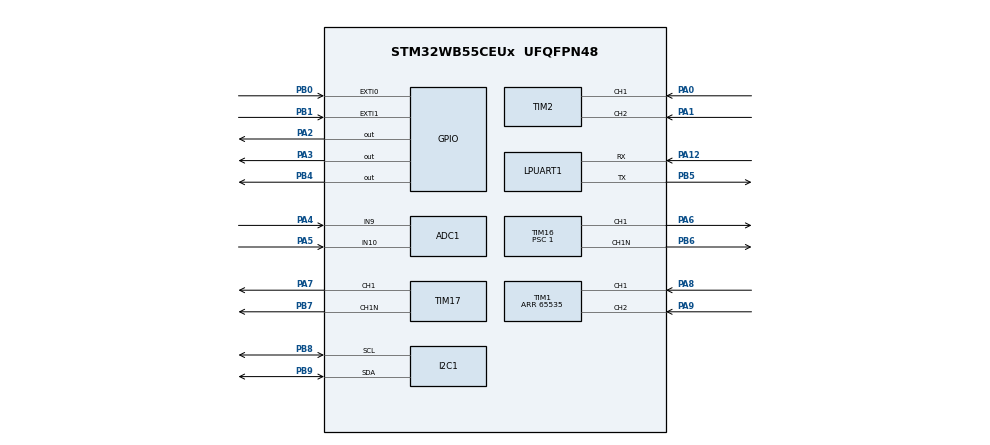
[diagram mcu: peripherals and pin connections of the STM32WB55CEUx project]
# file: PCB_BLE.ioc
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ADC1.Channel-0\#ChannelRegularConversion=ADC_CHANNEL_9
ADC1.Channel-1\#ChannelRegularConversion=ADC_CHANNEL_10
ADC1.ContinuousConvMode=ENABLE
ADC1.DMAContinuousRequests=ENABLE
ADC1.NbrOfConversion=2
ADC1.NbrOfConversionFlag=1
ADC1.OffsetNumber-0\#ChannelRegularConversion=ADC_OFFSET_NONE
ADC1.OffsetNumber-1\#ChannelRegularConversion=ADC_OFFSET_NONE
ADC1.Rank-0\#ChannelRegularConversion=1
ADC1.Rank-1\#ChannelRegularConversion=2
ADC1.SamplingTime-0\#ChannelRegularConversion=ADC_SAMPLETIME_640CYCLES_5
ADC1.SamplingTime-1\#ChannelRegularConversion=ADC_SAMPLETIME_640CYCLES_5
ADC1.master=1
Dma.ADC1.0.Direction=DMA_PERIPH_TO_MEMORY
Dma.ADC1.0.EventEnable=DISABLE
Dma.ADC1.0.Instance=DMA1_Channel1
Dma.ADC1.0.MemDataAlignment=DMA_MDATAALIGN_HALFWORD
Dma.ADC1.0.MemInc=DMA_MINC_ENABLE
Dma.ADC1.0.Mode=DMA_CIRCULAR
Dma.ADC1.0.PeriphDataAlignment=DMA_PDATAALIGN_HALFWORD
Dma.ADC1.0.PeriphInc=DMA_PINC_DISABLE
Dma.ADC1.0.Polarity=HAL_DMAMUX_REQ_GEN_RISING
Dma.ADC1.0.Priority=DMA_PRIORITY_LOW
Dma.ADC1.0.RequestNumber=1
Dma.ADC1.0.SignalID=NONE
Dma.ADC1.0.SyncEnable=DISABLE
Dma.ADC1.0.SyncPolarity=HAL_DMAMUX_SYNC_NO_EVENT
Dma.ADC1.0.SyncRequestNumber=1
Dma.ADC1.0.SyncSignalID=NONE
Dma.Request0=ADC1
FREERTOS.Tasks01=defaultTask,24,128,StartDefaultTask,Default,NULL,Dynamic,NULL,NULL
FREERTOS.configTOTAL_HEAP_SIZE=5000
I2C1.Timing=0x00B07CB4
LPTIM1.ClockPrescaler=LPTIM_PRESCALER_DIV128
Mcu.Family=STM32WB
Mcu.Name=STM32WB55CEUx
Mcu.Package=UFQFPN48
NVIC.ADC1_IRQn=true\:5\:0\:false\:false\:true\:true\:true\:true\:true
NVIC.DMA1_Channel1_IRQn=true\:5\:0\:false\:false\:true\:true\:false\:true\:true
NVIC.EXTI0_IRQn=true\:5\:0\:false\:false\:true\:true\:true\:true\:true
NVIC.HSEM_IRQn=true\:5\:0\:false\:false\:true\:true\:false\:true\:true
NVIC.IPCC_C1_RX_IRQn=true\:5\:0\:false\:false\:true\:true\:true\:true\:true
NVIC.IPCC_C1_TX_IRQn=true\:5\:0\:false\:false\:true\:true\:true\:true\:true
NVIC.LPTIM1_IRQn=true\:5\:0\:false\:false\:true\:true\:true\:true\:true
NVIC.PriorityGroup=NVIC_PRIORITYGROUP_4
NVIC.RTC_WKUP_IRQn=true\:5\:0\:false\:false\:true\:true\:true\:true\:true
OSC_IN.Mode=HSE-External-Oscillator
OSC_IN.Signal=RCC_OSC_IN
OSC_OUT.Mode=HSE-External-Oscillator
OSC_OUT.Signal=RCC_OSC_OUT
PA0.Signal=S_TIM2_CH1
PA1.Signal=S_TIM2_CH2
PA12.Mode=Asynchronous
PA12.Signal=LPUART1_RX
PA13.Mode=Serial_Wire
PA13.Signal=SYS_JTMS-SWDIO
PA14.Mode=Serial_Wire
PA14.Signal=SYS_JTCK-SWCLK
PA2.Signal=GPIO_Output
PA3.Signal=GPIO_Output
PA4.Signal=ADCx_IN9
PA5.Signal=ADCx_IN10
PA6.Signal=S_TIM16_CH1
PA7.Signal=S_TIM17_CH1
PA8.Signal=S_TIM1_CH1
PA9.Signal=S_TIM1_CH2
PB0.Signal=GPXTI0
PB1.Signal=GPXTI1
PB3.Signal=SYS_JTDO-SWO
PB4.Signal=GPIO_Output
PB5.Mode=Asynchronous
PB5.Signal=LPUART1_TX
PB6.Mode=PWM Generation1 CH1 CH1N
PB6.Signal=TIM16_CH1N
PB7.Mode=PWM Generation1 CH1 CH1N
PB7.Signal=TIM17_CH1N
PB8.Mode=I2C
PB8.Signal=I2C1_SCL
PB9.Mode=I2C
PB9.Signal=I2C1_SDA
PC14-OSC32_IN.Mode=LSE-External-Oscillator
PC14-OSC32_IN.Signal=RCC_OSC32_IN
PC15-OSC32_OUT.Mode=LSE-External-Oscillator
PC15-OSC32_OUT.Signal=RCC_OSC32_OUT
ProjectManager.HeapSize=0x200
ProjectManager.StackSize=0x400
ProjectManager.TargetToolchain=STM32CubeIDE
RCC.ADCFreq_Value=48000000
RCC.AHBFreq_Value=32000000
RCC.APB1Freq_Value=32000000
RCC.APB1TimFreq_Value=32000000
RCC.APB2Freq_Value=32000000
RCC.APB2TimFreq_Value=32000000
RCC.APB3Freq_Value=16000000
RCC.CortexFreq_Value=32000000
RCC.HCLKFreq_Value=32000000
RCC.HSE_VALUE=32000000
RCC.HSI48_VALUE=48000000
RCC.HSI_VALUE=16000000
RCC.PLLN=24
RCC.PLLR=RCC_PLLR_DIV3
RCC.PLLSAI1N=24
RCC.SYSCLKFreq_VALUE=32000000
RCC.SYSCLKSource=RCC_SYSCLKSOURCE_PLLCLK
RCC.USBFreq_Value=48000000
RCC.VCOOutputFreq_Value=96000000
RF1.Mode=RF1_Activate
RF1.Signal=RF_RF1
SH.ADCx_IN10.0=ADC1_IN10,IN10-Single-Ended
SH.ADCx_IN9.0=ADC1_IN9,IN9-Single-Ended
SH.S_TIM16_CH1.0=TIM16_CH1,PWM Generation1 CH1 CH1N
SH.S_TIM17_CH1.0=TIM17_CH1,PWM Generation1 CH1 CH1N
SH.S_TIM1_CH1.0=TIM1_CH1,Encoder_Interface
SH.S_TIM1_CH2.0=TIM1_CH2,Encoder_Interface
SH.S_TIM2_CH1.0=TIM2_CH1,Encoder_Interface
SH.S_TIM2_CH2.0=TIM2_CH2,Encoder_Interface
STM32_WPAN.BLE_DBG_APP_EN=1
STM32_WPAN.BLE_DBG_DIS_EN=1
STM32_WPAN.BLE_DBG_HRS_EN=1
STM32_WPAN.BLE_DBG_SVCCTL_EN=1
TIM1.AutoReloadPreload=TIM_AUTORELOAD_PRELOAD_ENABLE
TIM1.EncoderMode=TIM_ENCODERMODE_TI12
TIM1.IC1Filter=10
TIM1.Period=65535
TIM16.Channel=TIM_CHANNEL_1
TIM16.Period=1000-1
TIM16.Prescaler=1
TIM16.Pulse=0
TIM17.Channel=TIM_CHANNEL_1
VP_FREERTOS_VS_CMSIS_V2.Mode=CMSIS_V2
VP_HSEM_VS_HSEM.Mode=HSEM_Activate
VP_IPCC_VS_IPCC.Mode=IPCC_Activate
VP_LPTIM1_VS_LPTIM_counterModeInternalClock.Mode=Counts__internal_clock_event_00
VP_MEMORYMAP_VS_MEMORYMAP.Mode=CurAppReg
VP_RTC_VS_RTC_Activate.Mode=RTC_Enabled
VP_RTC_VS_RTC_WakeUp_intern.Mode=WakeUp
VP_STM32_WPAN_VS_BLE_HOST.Mode=STM32_WPAN_Enabled
VP_TIM16_VS_ClockSourceINT.Mode=Enable_Timer
VP_TIM17_VS_ClockSourceINT.Mode=Enable_Timer
VP_TINY_LPM_VS_TINY_LPM.Mode=TINY_LPM_Enabled
board=custom

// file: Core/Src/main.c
/* USER CODE BEGIN Header */
/**
  ******************************************************************************
  * @file           : main.c
  * @brief          : Main program body
  ******************************************************************************
  * @attention
  *
  * Copyright (c) 2025 STMicroelectronics.
  * All rights reserved.
  *
  * This software is licensed under terms that can be found in the LICENSE file
  * in the root directory of this software component.
  * If no LICENSE file comes with this software, it is provided AS-IS.
  *
  ******************************************************************************
  */
/* USER CODE END Header */
#include "main.h"
#include "cmsis_os.h"
#include "adc.h"
#include "dma.h"
#include "i2c.h"
#include "ipcc.h"
#include "lptim.h"
#include "usart.h"
#include "rf.h"
#include "rtc.h"
#include "tim.h"
#include "gpio.h"

/* USER CODE BEGIN Includes */
#include "timers.h"
#include "cmsis_os2.h"
#include "app_common.h"
#include <string.h>
#include "app_common.h"
#include "ble.h"
#include "ble_types.h"
#include "ble_const.h"
#include "ble_gap_aci.h"
#include "ble_gatt_aci.h"
#include "hci_tl.h"
#include "hrs_app.h"
#include "VL53L0X.h"
#include "stdio.h"
#include "sensor.h"
#include "moteur.h"
#include "LIDAR.h"
// ---------- Prototypes ----------
void SensorTask(void *argument);
void BleTask(void *argument);
/* USER CODE END Includes */

/* USER CODE BEGIN PTD */

extern osThreadId_t sensorTaskHandle;
extern osThreadId_t odomTaskHandle;
extern osThreadId_t lidarTaskHandle;
extern osThreadId_t defaultTaskHandle;
extern osThreadId_t TOFTaskHandle;
extern osThreadId_t comTaskHandle;

HAL_StatusTypeDef ID_SENSOR;
uint16_t position ;

extern Position pos ;

extern uint16_t distance;
extern statInfo_t_VL53L0X distanceStr;
System_state state = {0};
TOF capteur_tof ;
#define LPTIM_PERIOD_10MS 2500

volatile uint8_t dma_byte_buf[DMA_BYTE_BUF_SIZE];
Pos vue[N_ANGLES];  // tableau final des distances en mm
Cluster clusters[MAX_CLUSTERS];

int* last_count_g = 0;
int* last_count_d = 0;

/* USER CODE END PTD */

void SystemClock_Config(void);
void PeriphCommonClock_Config(void);
void MX_FREERTOS_Init(void);

int main(void)
{

  /* USER CODE BEGIN 1 */
	char msgBuffer[52];
	for (int i = 0; i < 52; i++) {
		msgBuffer[i] = ' ';
	}
  /* USER CODE END 1 */

  /* MCU Configuration--------------------------------------------------------*/

  /* Reset of all peripherals, Initializes the Flash interface and the Systick. */
  HAL_Init();
  /* Config code for STM32_WPAN (HSE Tuning must be done before system clock configuration) */
  MX_APPE_Config();

  /* Configure the system clock */
  SystemClock_Config();

  /* Configure the peripherals common clocks */
  PeriphCommonClock_Config();

  /* IPCC initialisation */
  MX_IPCC_Init();

  /* Initialize all configured peripherals */
  MX_GPIO_Init();
  MX_DMA_Init();
  MX_ADC1_Init();
  MX_LPTIM1_Init();
  MX_RTC_Init();
  MX_TIM1_Init();
  MX_TIM2_Init();
  MX_TIM16_Init();
  MX_TIM17_Init();
  MX_I2C1_Init();
  MX_LPUART1_UART_Init();
  MX_RF_Init();
  /* USER CODE BEGIN 2 */
  ID_SENSOR = ADXL343_Init();
  if (ID_SENSOR == HAL_OK)
  {
	  for (int i = 0;i<10;i++)
	  {
		   HAL_GPIO_TogglePin(GPIOA, GPIO_PIN_2);
		   //HAL_Delay(300);
	  }
  }

  ID_SENSOR = TCA9548A_Init();
    if (ID_SENSOR != HAL_OK)
    {
  	  for (int i = 0;i<20;i++)
  	  {
  		   HAL_GPIO_TogglePin(GPIOA, GPIO_PIN_2);
  		   //HAL_Delay(150);
  	  }
    }

  //Initialise the 4th TOF
  INIT_TOFS(&hi2c1);
  ///////
  CoreDebug->DEMCR |= CoreDebug_DEMCR_TRCENA_Msk;  // Active TRC
  DWT->CYCCNT = 0;                                  // Reset counter
  DWT->CTRL |= DWT_CTRL_CYCCNTENA_Msk;              // Active CYCCNT
  //Motor_Init();
  //Motor_Forward(500);
 // Motor_Ramp_L(&state, 600, 4);

  if (HAL_LPTIM_Counter_Start_IT(&hlptim1,LPTIM_PERIOD_10MS) != HAL_OK)
  {
      Error_Handler();
  }
  Encoder_Init();
  HAL_UART_Receive_DMA(&hlpuart1, (uint8_t *)dma_byte_buf, DMA_BYTE_BUF_SIZE);

  /* USER CODE END 2 */

  /* Init scheduler */
  osKernelInitialize();
  /* Init code for STM32_WPAN */
  MX_APPE_Init();
  /* Call init function for freertos objects (in cmsis_os2.c) */
  MX_FREERTOS_Init();

  /* Start scheduler */
  osKernelStart();

  /* We should never get here as control is now taken by the scheduler */

  /* Infinite loop */
  while (1)
  {

	}
}

void SystemClock_Config(void)
{
  RCC_OscInitTypeDef RCC_OscInitStruct = {0};
  RCC_ClkInitTypeDef RCC_ClkInitStruct = {0};

  /** Configure the main internal regulator output voltage
  */
  __HAL_PWR_VOLTAGESCALING_CONFIG(PWR_REGULATOR_VOLTAGE_SCALE1);

  /** Initializes the RCC Oscillators according to the specified parameters
  * in the RCC_OscInitTypeDef structure.
  */
  RCC_OscInitStruct.OscillatorType = RCC_OSCILLATORTYPE_HSI|RCC_OSCILLATORTYPE_LSI1
                              |RCC_OSCILLATORTYPE_HSE;
  RCC_OscInitStruct.HSEState = RCC_HSE_ON;
  RCC_OscInitStruct.HSIState = RCC_HSI_ON;
  RCC_OscInitStruct.HSICalibrationValue = RCC_HSICALIBRATION_DEFAULT;
  RCC_OscInitStruct.LSIState = RCC_LSI_ON;
  RCC_OscInitStruct.PLL.PLLState = RCC_PLL_ON;
  RCC_OscInitStruct.PLL.PLLSource = RCC_PLLSOURCE_HSE;
  RCC_OscInitStruct.PLL.PLLM = RCC_PLLM_DIV4;
  RCC_OscInitStruct.PLL.PLLN = 24;
  RCC_OscInitStruct.PLL.PLLP = RCC_PLLP_DIV2;
  RCC_OscInitStruct.PLL.PLLR = RCC_PLLR_DIV3;
  RCC_OscInitStruct.PLL.PLLQ = RCC_PLLQ_DIV2;
  if (HAL_RCC_OscConfig(&RCC_OscInitStruct) != HAL_OK)
  {
    Error_Handler();
  }

  /** Configure the SYSCLKSource, HCLK, PCLK1 and PCLK2 clocks dividers
  */
  RCC_ClkInitStruct.ClockType = RCC_CLOCKTYPE_HCLK4|RCC_CLOCKTYPE_HCLK2
                              |RCC_CLOCKTYPE_HCLK|RCC_CLOCKTYPE_SYSCLK
                              |RCC_CLOCKTYPE_PCLK1|RCC_CLOCKTYPE_PCLK2;
  RCC_ClkInitStruct.SYSCLKSource = RCC_SYSCLKSOURCE_PLLCLK;
  RCC_ClkInitStruct.AHBCLKDivider = RCC_SYSCLK_DIV1;
  RCC_ClkInitStruct.APB1CLKDivider = RCC_HCLK_DIV1;
  RCC_ClkInitStruct.APB2CLKDivider = RCC_HCLK_DIV1;
  RCC_ClkInitStruct.AHBCLK2Divider = RCC_SYSCLK_DIV2;
  RCC_ClkInitStruct.AHBCLK4Divider = RCC_SYSCLK_DIV1;

  if (HAL_RCC_ClockConfig(&RCC_ClkInitStruct, FLASH_LATENCY_3) != HAL_OK)
  {
    Error_Handler();
  }
}

void PeriphCommonClock_Config(void)
{
  RCC_PeriphCLKInitTypeDef PeriphClkInitStruct = {0};

  /** Initializes the peripherals clock
  */
  PeriphClkInitStruct.PeriphClockSelection = RCC_PERIPHCLK_SMPS|RCC_PERIPHCLK_RFWAKEUP;
  PeriphClkInitStruct.RFWakeUpClockSelection = RCC_RFWKPCLKSOURCE_HSE_DIV1024;
  PeriphClkInitStruct.SmpsClockSelection = RCC_SMPSCLKSOURCE_HSI;
  PeriphClkInitStruct.SmpsDivSelection = RCC_SMPSCLKDIV_RANGE1;

  if (HAL_RCCEx_PeriphCLKConfig(&PeriphClkInitStruct) != HAL_OK)
  {
    Error_Handler();
  }
}

/* USER CODE BEGIN 4 */
void HAL_ADC_ConvCpltCallback(ADC_HandleTypeDef* hadc)
{
    if (hadc->Instance == ADC1)
    {
    }
}
extern osSemaphoreId_t i2cSem;
extern osSemaphoreId_t chockSem;
extern osSemaphoreId_t UARTSem;

void HAL_UART_RxCpltCallback(UART_HandleTypeDef *huart)
{
    if(huart->Instance == LPUART1)
    {
  	  osSemaphoreRelease(UARTSem);
    }
}

void HAL_LPTIM_AutoReloadMatchCallback(LPTIM_HandleTypeDef *hlptim)
{
    if (hlptim->Instance == LPTIM1)
    {
    	  //Control_Speed(10.0f,0.01);

    	//Update_Encoder_Vitesse(pos,&last_count_d,&last_count_g);

    	/*
    	// PID gauche
		float u_g = PID_Update(&pid_vitesse_G, pid_vitesse_G, pos.Vitesse_G, 0.001f);
		int pwm_g = (int)(500 + u_g * 500);
		__HAL_TIM_SET_COMPARE(&htim1, TIM_CHANNEL_1, pwm_g);

		// PID droit
		float u_d = PID_Update(&pid_vitesse_D, pid_vitesse_D, pos.Vitesse_D, 0.001f);
		int pwm_d = (int)(500 + u_d * 500);
		__HAL_TIM_SET_COMPARE(&htim2, TIM_CHANNEL_1, pwm_d);
		*/
    }
}

void HAL_GPIO_EXTI_Callback(uint16_t GPIO_Pin)
{
    if (GPIO_Pin == GPIO_PIN_0) // Vérifie que c'est bien le pin attendu
    {
    	//__HAL_GPIO_EXTI_CLEAR_IT(GPIO_PIN_0);
    	osSemaphoreRelease(chockSem);

    }
}

void HAL_I2C_MemRxCpltCallback(I2C_HandleTypeDef *hi2c)
{
    if (hi2c->Instance == I2C1) {
    	//osSemaphoreRelease(i2cSem);
    }
}

/* USER CODE END 4 */

void Error_Handler(void)
{
  __disable_irq();
  while (1)
  {
  }
}

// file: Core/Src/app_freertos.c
/* USER CODE BEGIN Header */
/**
  ******************************************************************************
  * File Name          : app_freertos.c
  * Description        : Code for freertos applications
  ******************************************************************************
  * @attention
  *
  * Copyright (c) 2025 STMicroelectronics.
  * All rights reserved.
  *
  * This software is licensed under terms that can be found in the LICENSE file
  * in the root directory of this software component.
  * If no LICENSE file comes with this software, it is provided AS-IS.
  *
  ******************************************************************************
  */
/* USER CODE END Header */

#include "FreeRTOS.h"
#include "task.h"
#include "main.h"
#include "cmsis_os.h"

/* USER CODE BEGIN Includes */
#include "VL53L0X.h"
#include "sensor.h"
#include "moteur.h"
#include "lidar.h"
#include "main.h"
#include "cmsis_os.h"
#include "adc.h"
#include "dma.h"
#include "i2c.h"
#include "ipcc.h"
#include "lptim.h"
#include "usart.h"
#include "rf.h"
#include "rtc.h"
#include "tim.h"
#include "gpio.h"
osThreadId_t ControlLoopTaskHandle; //
osThreadId_t odomTaskHandle;
osThreadId_t lidarTaskHandle;
osThreadId_t MainLogicTaskHandle; //
osThreadId_t SafetyTaskHandle; //
osThreadId_t comTaskHandle;

extern ADC_HandleTypeDef hadc1;
extern System_state state ;

/* USER CODE END Includes */

/* USER CODE BEGIN PTD */
#define SAFETY_TASK_PERIOD_MS 10

uint16_t distance;

Position pos = {0};

#define ADC_BUFFER_SIZE 2
uint16_t adc_buffer[ADC_BUFFER_SIZE];

Measure m1;
Position robot;

osSemaphoreId_t sem_sensor;
osSemaphoreId_t sem_3axis;
osMutexId_t i2cMutex;
osMutexId_t motorMutex;

extern Pos vue[N_ANGLES];
osMutexId_t myMutexHandle;
const osMutexAttr_t myMutexAttr = {
  .name = "myMutex"
};

osMutexId_t motorMutexHandle;
const osMutexAttr_t motorAttr = {
  .name = "motorMutex"
};

osSemaphoreId_t i2cSem;
osSemaphoreId_t chockSem;
osSemaphoreId_t UARTSem;

extern TOF capteur_tof ;

float angle ;

uint32_t t1;
uint32_t t2;

statInfo_t_VL53L0X distanceStr;

float mean_velo = 0;

extern float velocity;

#define ALPHA  0.95
#define TARGET 10.0
/* USER CODE END PTD */

/* Definitions for defaultTask */
osThreadId_t defaultTaskHandle;
const osThreadAttr_t defaultTask_attributes = {
  .name = "defaultTask",
  .priority = (osPriority_t) osPriorityNormal,
  .stack_size = 128 * 4
};

/* USER CODE BEGIN FunctionPrototypes */
void Task_main_loop(void *argument);
void Task_odom(void *argument);
void Task_lidar(void *argument);
void Task_com(void *argument);
void Task_control_loop(void *argument);
void Task_safety(void *argument);
/* USER CODE END FunctionPrototypes */

void StartDefaultTask(void *argument);

void MX_FREERTOS_Init(void); /* (MISRA C 2004 rule 8.1) */

/* Hook prototypes */
void configureTimerForRunTimeStats(void);
unsigned long getRunTimeCounterValue(void);

/* USER CODE BEGIN 1 */
/* Functions needed when configGENERATE_RUN_TIME_STATS is on */
__weak void configureTimerForRunTimeStats(void)
{

}

__weak unsigned long getRunTimeCounterValue(void)
{
return 0;
}
/* USER CODE END 1 */

void MX_FREERTOS_Init(void) {

  /* Create the thread(s) */
  /* creation of defaultTask */
  defaultTaskHandle = osThreadNew(StartDefaultTask, NULL, &defaultTask_attributes);

  /* USER CODE BEGIN RTOS_THREADS */
  const osThreadAttr_t MainLogicTaskAttr = {
      .name = "MainLogic",
      .priority = osPriorityAboveNormal,
      .stack_size = 512   // CMSIS expects bytes
  };

  MainLogicTaskHandle = osThreadNew(Task_main_loop, NULL, &MainLogicTaskAttr);
  if (MainLogicTaskHandle == NULL) {
      Error_Handler();
  }

  const osThreadAttr_t odomTaskAttr = {
   	 .name = "Task_odom",
  	 .priority = osPriorityAboveNormal,
  	 .stack_size = 512
  };
  odomTaskHandle = osThreadNew(Task_odom, NULL, &odomTaskAttr);
  if (odomTaskHandle == NULL) {
 	 Error_Handler();
  }

  const osThreadAttr_t lidarTaskAttr = {
     	 .name = "Task_lidar",
    	 .priority = osPriorityHigh,
    	 .stack_size = 1536
  };
  lidarTaskHandle = osThreadNew(Task_lidar, NULL, &lidarTaskAttr);
  if (lidarTaskHandle == NULL) {
 	 Error_Handler();
  }

  const osThreadAttr_t comTaskAttr = {
     	 .name = "Task_com",
    	 .priority = osPriorityHigh,
    	 .stack_size = 512
  };
  comTaskHandle = osThreadNew(Task_com, NULL, &comTaskAttr);
  if (comTaskHandle == NULL) {
 	 Error_Handler();
  }

  const osThreadAttr_t ControlLoopTaskAttr = {
     	 .name = "Task_control_loop",
    	 .priority = osPriorityHigh,
    	 .stack_size = 512
  };
  ControlLoopTaskHandle = osThreadNew(Task_control_loop, NULL, &ControlLoopTaskAttr);
  if (ControlLoopTaskHandle == NULL) {
 	 Error_Handler();
  }

  const osThreadAttr_t SafetyTaskAttr = {
     	 .name = "Task_safety",
    	 .priority = osPriorityRealtime,
    	 .stack_size = 1536
  };
  SafetyTaskHandle = osThreadNew(Task_safety, NULL, &SafetyTaskAttr);
  if (SafetyTaskHandle == NULL) {
    	 Error_Handler();
  }

  myMutexHandle = osMutexNew(&myMutexAttr);
  i2cSem = osSemaphoreNew(1, 1, NULL);
  chockSem = osSemaphoreNew(1, 0, NULL);
  UARTSem = osSemaphoreNew(1, 0, NULL);
  motorMutexHandle = osMutexNew(&motorAttr);

  /* USER CODE END RTOS_THREADS */

}

void StartDefaultTask(void *argument)
{
  /* USER CODE BEGIN StartDefaultTask */
  /* Infinite loop */
  for(;;)
  {
    osDelay(100);
  }
  /* USER CODE END StartDefaultTask */
}

/* USER CODE BEGIN Application */

void Task_safety(void *argument)
{
    UNUSED(argument);
    uint8_t source;
    INIT_ADC(&adc_buffer,ADC_BUFFER_SIZE);

    // Remise à zéro du compteur au début
    for (;;)
    {
    	//cycles = DWT->CYCCNT;
    	//---------MESURE TOF---------//
        osMutexAcquire(i2cSem, pdMS_TO_TICKS(200));
        t1 = DWT->CYCCNT;
    	mesure_TOF(&capteur_tof);
    	t2 = DWT->CYCCNT - t1;
        osMutexRelease(i2cSem);
        //------------------//

        if (capteur_tof.front > 200)
        {
        	state.space = 1 ;
        	Motor_Reverse_R(&state,200);
        	Motor_Reverse_L(&state,200);

        }
        else if (capteur_tof.back > 200)
        {
        	state.space = 2 ;
        	Motor_Reverse_R(&state,200);
        	Motor_Reverse_L(&state,200);

        }
        else
        {
        	/*
        	temps = DWT->CYCCNT-cycles;
            Control_Speed(TARGET,temps);
            cycles = DWT->CYCCNT;
            */
        	Motor_Forward_R(&state,300);
        	Motor_Forward_L(&state,300);
        	state.space = 0 ;
        }
        /*
		if (state.space > 0)
		{
			Motor_Forward_R(&state,100);
		}
		*/

	  mean_velo =  ALPHA * mean_velo + (1-ALPHA)*velocity;

		//temps = DWT->CYCCNT-cycles;

		osDelay(20);

    }
}

void Task_main_loop(void *argument)
{
    UNUSED(argument);
    // Remise à zéro du compteur au début
    for (;;)
    {
    	osDelay(10);

    }

    // Ici la tâche peut continuer ou se terminer
}
void Task_odom(void *argument)
{
  UNUSED(argument);
  for (;;)
  {

   osDelay(10);
  }
}

void Task_lidar(void *argument)
{
  UNUSED(argument);
  for (;;)
  {

	  osMutexAcquire(UARTSem, pdMS_TO_TICKS(200));
	  YD_Parser_MainLoop(&vue);
	  segment_points(&vue, 360);
	  osMutexRelease(UARTSem);
	  osDelay(10);
	  //osMutexAcquire(i2cSem, pdMS_TO_TICKS(200));
      //UPDATE_V_I(&m1,&adc_buffer);
      //osMutexRelease(i2cSem);

	  //YD_Parser_MainLoop(&vue);

  }
}

void Task_com(void *argument)
{

  UNUSED(argument);
  for (;;)
  {
	    //osDelay(10);
  }
}

void Task_control_loop(void *argument)
{
  UNUSED(argument);
  uint8_t source;
  TickType_t lastWakeTime = xTaskGetTickCount();
  for (;;)
  {   if (state.space == 0)
  	  {
	  	  //Motor_Forward(400);
  	  }

	  pos.angle_r = Encoder_UpdateAngle(&htim2);
	  pos.angle_l =Encoder_UpdateAngle(&htim1);
	  vTaskDelayUntil(&lastWakeTime, pdMS_TO_TICKS(10));
  }
}
/* USER CODE END Application */
